VERSION 5.7 ;
  NOWIREEXTENSIONATPIN ON ;
  DIVIDERCHAR "/" ;
  BUSBITCHARS "[]" ;
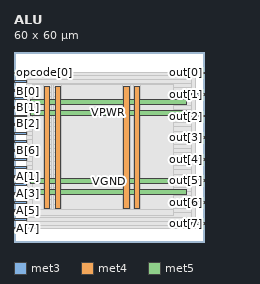
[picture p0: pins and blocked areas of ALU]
MACRO ALU
  CLASS BLOCK ;
  FOREIGN ALU ;
  ORIGIN 0.000 0.000 ;
  SIZE 60.000 BY 60.000 ;
  PIN A[0]
    DIRECTION INPUT ;
    USE SIGNAL ;
    ANTENNAGATEAREA 0.126000 ;
    PORT
      LAYER met3 ;
        RECT 0.000 23.160 4.000 23.760 ;
    END
  END A[0]
  PIN A[1]
    DIRECTION INPUT ;
    USE SIGNAL ;
    ANTENNAGATEAREA 0.213000 ;
    PORT
      LAYER met3 ;
        RECT 0.000 20.440 4.000 21.040 ;
    END
  END A[1]
  PIN A[2]
    DIRECTION INPUT ;
    USE SIGNAL ;
    ANTENNAGATEAREA 0.213000 ;
    PORT
      LAYER met3 ;
        RECT 0.000 17.720 4.000 18.320 ;
    END
  END A[2]
  PIN A[3]
    DIRECTION INPUT ;
    USE SIGNAL ;
    ANTENNAGATEAREA 0.213000 ;
    PORT
      LAYER met3 ;
        RECT 0.000 15.000 4.000 15.600 ;
    END
  END A[3]
  PIN A[4]
    DIRECTION INPUT ;
    USE SIGNAL ;
    ANTENNAGATEAREA 0.213000 ;
    PORT
      LAYER met3 ;
        RECT 0.000 12.280 4.000 12.880 ;
    END
  END A[4]
  PIN A[5]
    DIRECTION INPUT ;
    USE SIGNAL ;
    ANTENNAGATEAREA 0.213000 ;
    PORT
      LAYER met3 ;
        RECT 0.000 9.560 4.000 10.160 ;
    END
  END A[5]
  PIN A[6]
    DIRECTION INPUT ;
    USE SIGNAL ;
    ANTENNAGATEAREA 0.213000 ;
    PORT
      LAYER met3 ;
        RECT 0.000 6.840 4.000 7.440 ;
    END
  END A[6]
  PIN A[7]
    DIRECTION INPUT ;
    USE SIGNAL ;
    ANTENNAGATEAREA 0.196500 ;
    PORT
      LAYER met3 ;
        RECT 0.000 4.120 4.000 4.720 ;
    END
  END A[7]
  PIN B[0]
    DIRECTION INPUT ;
    USE SIGNAL ;
    ANTENNAGATEAREA 0.213000 ;
    PORT
      LAYER met3 ;
        RECT 0.000 44.920 4.000 45.520 ;
    END
  END B[0]
  PIN B[1]
    DIRECTION INPUT ;
    USE SIGNAL ;
    ANTENNAGATEAREA 0.213000 ;
    PORT
      LAYER met3 ;
        RECT 0.000 42.200 4.000 42.800 ;
    END
  END B[1]
  PIN B[2]
    DIRECTION INPUT ;
    USE SIGNAL ;
    ANTENNAGATEAREA 0.213000 ;
    PORT
      LAYER met3 ;
        RECT 0.000 39.480 4.000 40.080 ;
    END
  END B[2]
  PIN B[3]
    DIRECTION INPUT ;
    USE SIGNAL ;
    ANTENNAGATEAREA 0.213000 ;
    PORT
      LAYER met3 ;
        RECT 0.000 36.760 4.000 37.360 ;
    END
  END B[3]
  PIN B[4]
    DIRECTION INPUT ;
    USE SIGNAL ;
    ANTENNAGATEAREA 0.213000 ;
    PORT
      LAYER met3 ;
        RECT 0.000 34.040 4.000 34.640 ;
    END
  END B[4]
  PIN B[5]
    DIRECTION INPUT ;
    USE SIGNAL ;
    ANTENNAGATEAREA 0.213000 ;
    PORT
      LAYER met3 ;
        RECT 0.000 31.320 4.000 31.920 ;
    END
  END B[5]
  PIN B[6]
    DIRECTION INPUT ;
    USE SIGNAL ;
    ANTENNAGATEAREA 0.213000 ;
    PORT
      LAYER met3 ;
        RECT 0.000 28.600 4.000 29.200 ;
    END
  END B[6]
  PIN B[7]
    DIRECTION INPUT ;
    USE SIGNAL ;
    ANTENNAGATEAREA 0.196500 ;
    PORT
      LAYER met3 ;
        RECT 0.000 25.880 4.000 26.480 ;
    END
  END B[7]
  PIN VGND
    DIRECTION INOUT ;
    USE GROUND ;
    PORT
      LAYER met4 ;
        RECT 13.020 10.640 14.620 49.200 ;
    END
    PORT
      LAYER met4 ;
        RECT 38.020 10.640 39.620 49.200 ;
    END
    PORT
      LAYER met5 ;
        RECT 5.280 18.380 54.520 19.980 ;
    END
    PORT
      LAYER met5 ;
        RECT 5.280 43.380 54.520 44.980 ;
    END
  END VGND
  PIN VPWR
    DIRECTION INOUT ;
    USE POWER ;
    PORT
      LAYER met4 ;
        RECT 9.720 10.640 11.320 49.200 ;
    END
    PORT
      LAYER met4 ;
        RECT 34.720 10.640 36.320 49.200 ;
    END
    PORT
      LAYER met5 ;
        RECT 5.280 15.080 54.520 16.680 ;
    END
    PORT
      LAYER met5 ;
        RECT 5.280 40.080 54.520 41.680 ;
    END
  END VPWR
  PIN opcode[0]
    DIRECTION INPUT ;
    USE SIGNAL ;
    ANTENNAGATEAREA 0.495000 ;
    PORT
      LAYER met3 ;
        RECT 0.000 53.080 4.000 53.680 ;
    END
  END opcode[0]
  PIN opcode[1]
    DIRECTION INPUT ;
    USE SIGNAL ;
    ANTENNAGATEAREA 0.247500 ;
    PORT
      LAYER met3 ;
        RECT 0.000 50.360 4.000 50.960 ;
    END
  END opcode[1]
  PIN opcode[2]
    DIRECTION INPUT ;
    USE SIGNAL ;
    ANTENNAGATEAREA 0.247500 ;
    PORT
      LAYER met3 ;
        RECT 0.000 47.640 4.000 48.240 ;
    END
  END opcode[2]
  PIN out[0]
    DIRECTION OUTPUT ;
    USE SIGNAL ;
    ANTENNADIFFAREA 0.445500 ;
    PORT
      LAYER met3 ;
        RECT 56.000 53.080 60.000 53.680 ;
    END
  END out[0]
  PIN out[1]
    DIRECTION OUTPUT ;
    USE SIGNAL ;
    ANTENNADIFFAREA 0.445500 ;
    PORT
      LAYER met3 ;
        RECT 56.000 46.280 60.000 46.880 ;
    END
  END out[1]
  PIN out[2]
    DIRECTION OUTPUT ;
    USE SIGNAL ;
    ANTENNADIFFAREA 0.445500 ;
    PORT
      LAYER met3 ;
        RECT 56.000 39.480 60.000 40.080 ;
    END
  END out[2]
  PIN out[3]
    DIRECTION OUTPUT ;
    USE SIGNAL ;
    ANTENNADIFFAREA 0.445500 ;
    PORT
      LAYER met3 ;
        RECT 56.000 32.680 60.000 33.280 ;
    END
  END out[3]
  PIN out[4]
    DIRECTION OUTPUT ;
    USE SIGNAL ;
    ANTENNADIFFAREA 0.445500 ;
    PORT
      LAYER met3 ;
        RECT 56.000 25.880 60.000 26.480 ;
    END
  END out[4]
  PIN out[5]
    DIRECTION OUTPUT ;
    USE SIGNAL ;
    ANTENNADIFFAREA 0.445500 ;
    PORT
      LAYER met3 ;
        RECT 56.000 19.080 60.000 19.680 ;
    END
  END out[5]
  PIN out[6]
    DIRECTION OUTPUT ;
    USE SIGNAL ;
    ANTENNADIFFAREA 0.445500 ;
    PORT
      LAYER met3 ;
        RECT 56.000 12.280 60.000 12.880 ;
    END
  END out[6]
  PIN out[7]
    DIRECTION OUTPUT ;
    USE SIGNAL ;
    ANTENNADIFFAREA 1.336500 ;
    PORT
      LAYER met3 ;
        RECT 56.000 5.480 60.000 6.080 ;
    END
  END out[7]
  OBS
      LAYER nwell ;
        RECT 5.330 10.795 54.470 49.045 ;
      LAYER li1 ;
        RECT 5.520 10.795 54.280 49.045 ;
      LAYER met1 ;
        RECT 4.210 9.900 57.430 49.200 ;
      LAYER met2 ;
        RECT 4.230 4.235 57.400 53.565 ;
      LAYER met3 ;
        RECT 4.400 52.680 55.600 53.545 ;
        RECT 3.990 51.360 56.000 52.680 ;
        RECT 4.400 49.960 56.000 51.360 ;
        RECT 3.990 48.640 56.000 49.960 ;
        RECT 4.400 47.280 56.000 48.640 ;
        RECT 4.400 47.240 55.600 47.280 ;
        RECT 3.990 45.920 55.600 47.240 ;
        RECT 4.400 45.880 55.600 45.920 ;
        RECT 4.400 44.520 56.000 45.880 ;
        RECT 3.990 43.200 56.000 44.520 ;
        RECT 4.400 41.800 56.000 43.200 ;
        RECT 3.990 40.480 56.000 41.800 ;
        RECT 4.400 39.080 55.600 40.480 ;
        RECT 3.990 37.760 56.000 39.080 ;
        RECT 4.400 36.360 56.000 37.760 ;
        RECT 3.990 35.040 56.000 36.360 ;
        RECT 4.400 33.680 56.000 35.040 ;
        RECT 4.400 33.640 55.600 33.680 ;
        RECT 3.990 32.320 55.600 33.640 ;
        RECT 4.400 32.280 55.600 32.320 ;
        RECT 4.400 30.920 56.000 32.280 ;
        RECT 3.990 29.600 56.000 30.920 ;
        RECT 4.400 28.200 56.000 29.600 ;
        RECT 3.990 26.880 56.000 28.200 ;
        RECT 4.400 25.480 55.600 26.880 ;
        RECT 3.990 24.160 56.000 25.480 ;
        RECT 4.400 22.760 56.000 24.160 ;
        RECT 3.990 21.440 56.000 22.760 ;
        RECT 4.400 20.080 56.000 21.440 ;
        RECT 4.400 20.040 55.600 20.080 ;
        RECT 3.990 18.720 55.600 20.040 ;
        RECT 4.400 18.680 55.600 18.720 ;
        RECT 4.400 17.320 56.000 18.680 ;
        RECT 3.990 16.000 56.000 17.320 ;
        RECT 4.400 14.600 56.000 16.000 ;
        RECT 3.990 13.280 56.000 14.600 ;
        RECT 4.400 11.880 55.600 13.280 ;
        RECT 3.990 10.560 56.000 11.880 ;
        RECT 4.400 9.160 56.000 10.560 ;
        RECT 3.990 7.840 56.000 9.160 ;
        RECT 4.400 6.480 56.000 7.840 ;
        RECT 4.400 6.440 55.600 6.480 ;
        RECT 3.990 5.120 55.600 6.440 ;
        RECT 4.400 5.080 55.600 5.120 ;
        RECT 4.400 4.255 56.000 5.080 ;
      LAYER met4 ;
        RECT 5.815 49.600 50.305 50.145 ;
        RECT 5.815 10.240 9.320 49.600 ;
        RECT 11.720 10.240 12.620 49.600 ;
        RECT 15.020 10.240 34.320 49.600 ;
        RECT 36.720 10.240 37.620 49.600 ;
        RECT 40.020 10.240 50.305 49.600 ;
        RECT 5.815 8.335 50.305 10.240 ;
  END
END ALU
END LIBRARY

